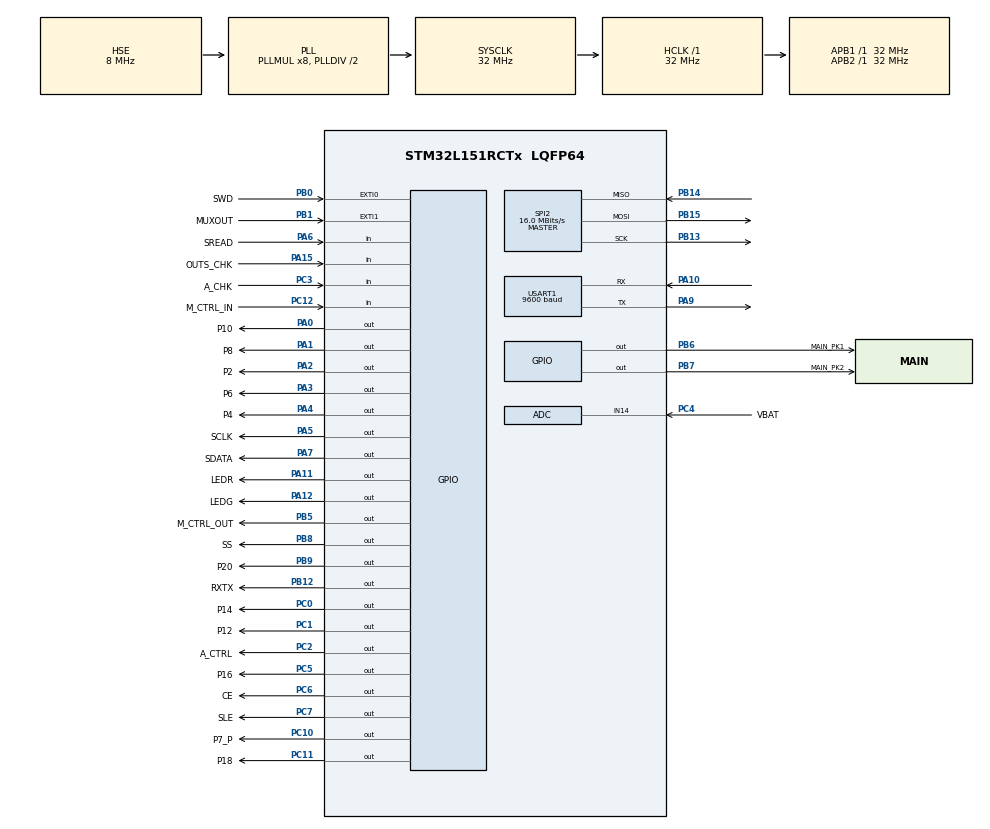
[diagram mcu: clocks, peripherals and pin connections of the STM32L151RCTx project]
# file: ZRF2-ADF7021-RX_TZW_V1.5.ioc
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ADC.Channel-0\#ChannelRegularConversion=ADC_CHANNEL_14
ADC.ContinuousConvMode=DISABLE
ADC.DataAlign=ADC_DATAALIGN_RIGHT
ADC.DiscontinuousConvMode=DISABLE
ADC.EnableAnalogWatchDog=false
ADC.ExternalTrigConv=ADC_SOFTWARE_START
ADC.InjNumberOfConversion=0
ADC.NbrOfConversion=1
ADC.Rank-0\#ChannelRegularConversion=1
ADC.SamplingTime-0\#ChannelRegularConversion=ADC_SAMPLETIME_192CYCLES
ADC.ScanConvMode=ADC_SCAN_DISABLE
Dma.ADC.0.Direction=DMA_PERIPH_TO_MEMORY
Dma.ADC.0.Instance=DMA1_Channel1
Dma.ADC.0.MemDataAlignment=DMA_MDATAALIGN_HALFWORD
Dma.ADC.0.MemInc=DMA_MINC_ENABLE
Dma.ADC.0.Mode=DMA_NORMAL
Dma.ADC.0.PeriphDataAlignment=DMA_PDATAALIGN_HALFWORD
Dma.ADC.0.PeriphInc=DMA_PINC_DISABLE
Dma.ADC.0.Priority=DMA_PRIORITY_LOW
Dma.Request0=ADC
FREERTOS.Tasks01=defaultTask,0,256,StartDefaultTask,Default,NULL,Dynamic,NULL,NULL
FREERTOS.configMAX_PRIORITIES=9
FREERTOS.configMINIMAL_STACK_SIZE=128
FREERTOS.configTOTAL_HEAP_SIZE=16000
FREERTOS.configUSE_NEWLIB_REENTRANT=1
FREERTOS.configUSE_TIMERS=1
Mcu.Family=STM32L1
Mcu.Name=STM32L151RCTx
Mcu.Package=LQFP64
NVIC.ADC1_IRQn=true\:5\:0\:false\:false\:true\:true\:true\:true\:true
NVIC.DMA1_Channel1_IRQn=true\:5\:0\:false\:false\:true\:true\:true\:true\:true
NVIC.EXTI0_IRQn=true\:5\:0\:false\:false\:true\:true\:true\:true\:true
NVIC.EXTI1_IRQn=true\:5\:0\:true\:false\:true\:true\:true\:true\:true
NVIC.PriorityGroup=NVIC_PRIORITYGROUP_4
NVIC.TIM11_IRQn=true\:5\:0\:false\:false\:true\:true\:true\:true\:true
NVIC.TIM2_IRQn=true\:15\:0\:false\:false\:true\:false\:false\:true\:true
NVIC.TimeBase=TIM2_IRQn
NVIC.TimeBaseIP=TIM2
NVIC.USART1_IRQn=true\:5\:0\:true\:false\:true\:true\:true\:true\:true
PA0-WKUP1.GPIO_Label=P10
PA0-WKUP1.Signal=GPIO_Output
PA1.GPIO_Label=P8
PA1.Signal=GPIO_Output
PA10.Mode=Asynchronous
PA10.Signal=USART1_RX
PA11.GPIO_Label=LEDR
PA11.Signal=GPIO_Output
PA12.GPIO_Label=LEDG
PA12.Signal=GPIO_Output
PA13.Mode=Serial_Wire
PA13.Signal=SYS_JTMS-SWDIO
PA14.Mode=Serial_Wire
PA14.Signal=SYS_JTCK-SWCLK
PA15.GPIO_Label=OUTS_CHK
PA15.GPIO_PuPd=GPIO_PULLUP
PA15.Signal=GPIO_Input
PA2.GPIO_Label=P2
PA2.Signal=GPIO_Output
PA3.GPIO_Label=P6
PA3.Signal=GPIO_Output
PA4.GPIO_Label=P4
PA4.Signal=GPIO_Output
PA5.GPIO_Label=SCLK
PA5.GPIO_Speed=GPIO_SPEED_FREQ_VERY_HIGH
PA5.Signal=GPIO_Output
PA6.GPIO_Label=SREAD
PA6.GPIO_PuPd=GPIO_PULLUP
PA6.Signal=GPIO_Input
PA7.GPIO_Label=SDATA
PA7.GPIO_Speed=GPIO_SPEED_FREQ_VERY_HIGH
PA7.Signal=GPIO_Output
PA9.Mode=Asynchronous
PA9.Signal=USART1_TX
PB0.GPIO_Label=SWD
PB0.GPIO_ModeDefaultEXTI=GPIO_MODE_IT_RISING
PB0.GPIO_PuPd=GPIO_NOPULL
PB0.Signal=GPXTI0
PB1.GPIO_Label=MUXOUT
PB1.GPIO_PuPd=GPIO_NOPULL
PB1.Signal=GPXTI1
PB12.GPIO_Label=RXTX
PB12.GPIO_PuPd=GPIO_NOPULL
PB12.GPIO_Speed=GPIO_SPEED_FREQ_VERY_HIGH
PB12.PinState=GPIO_PIN_RESET
PB12.Signal=GPIO_Output
PB13.Mode=Full_Duplex_Master
PB13.Signal=SPI2_SCK
PB14.Mode=Full_Duplex_Master
PB14.Signal=SPI2_MISO
PB15.Mode=Full_Duplex_Master
PB15.Signal=SPI2_MOSI
PB5.GPIO_Label=M_CTRL_OUT
PB5.GPIO_Speed=GPIO_SPEED_FREQ_MEDIUM
PB5.Signal=GPIO_Output
PB6.GPIO_Label=MAIN_PK1
PB6.Signal=GPIO_Output
PB7.GPIO_Label=MAIN_PK2
PB7.Signal=GPIO_Output
PB8.GPIO_Label=SS
PB8.GPIO_Speed=GPIO_SPEED_FREQ_VERY_HIGH
PB8.Signal=GPIO_Output
PB9.GPIO_Label=P20
PB9.Signal=GPIO_Output
PC0.GPIO_Label=P14
PC0.Signal=GPIO_Output
PC1.GPIO_Label=P12
PC1.Signal=GPIO_Output
PC10.GPIO_Label=P7_P
PC10.Signal=GPIO_Output
PC11.GPIO_Label=P18
PC11.Signal=GPIO_Output
PC12.GPIO_Label=M_CTRL_IN
PC12.GPIO_PuPd=GPIO_PULLUP
PC12.Signal=GPIO_Input
PC2.GPIO_Label=A_CTRL
PC2.PinState=GPIO_PIN_SET
PC2.Signal=GPIO_Output
PC3.GPIO_Label=A_CHK
PC3.GPIO_PuPd=GPIO_NOPULL
PC3.Signal=GPIO_Input
PC4.GPIO_Label=VBAT
PC4.Mode=IN14
PC4.Signal=ADC_IN14
PC5.GPIO_Label=P16
PC5.Signal=GPIO_Output
PC6.GPIO_Label=CE
PC6.GPIO_Speed=GPIO_SPEED_FREQ_VERY_HIGH
PC6.Signal=GPIO_Output
PC7.GPIO_Label=SLE
PC7.GPIO_Speed=GPIO_SPEED_FREQ_VERY_HIGH
PC7.Signal=GPIO_Output
PH0-OSC_IN.Mode=HSE-External-Oscillator
PH0-OSC_IN.Signal=RCC_OSC_IN
PH1-OSC_OUT.Mode=HSE-External-Oscillator
PH1-OSC_OUT.Signal=RCC_OSC_OUT
ProjectManager.HeapSize=0x200
ProjectManager.StackSize=0x400
ProjectManager.TargetToolchain=STM32CubeIDE
RCC.48MHZClocksFreq_Value=32000000
RCC.AHBFreq_Value=32000000
RCC.APB1Freq_Value=32000000
RCC.APB1TimFreq_Value=32000000
RCC.APB2Freq_Value=32000000
RCC.APB2TimFreq_Value=32000000
RCC.EnbaleCSS=true
RCC.FLatency=FLASH_LATENCY_1
RCC.HCLKFreq_Value=32000000
RCC.HSE_VALUE=8000000
RCC.HSI_VALUE=16000000
RCC.LSE_VALUE=32768
RCC.MSI_VALUE=2097000
RCC.PLLMUL=RCC_PLL_MUL8
RCC.PLLSourceVirtual=RCC_PLLSOURCE_HSE
RCC.PREFETCH_ENABLE=1
RCC.SYSCLKFreq_VALUE=32000000
RCC.SYSCLKSource=RCC_SYSCLKSOURCE_PLLCLK
RCC.VCOOutputFreq_Value=64000000
RCC.VDD_VALUE=3.3
SPI2.CalculateBaudRate=16.0 MBits/s
SPI2.Direction=SPI_DIRECTION_2LINES
SPI2.Mode=SPI_MODE_MASTER
SPI2.VirtualType=VM_MASTER
TIM11.Period=10-1
TIM11.Prescaler=32000-1
USART1.BaudRate=9600
USART1.Mode=MODE_TX_RX
USART1.OverSampling=UART_OVERSAMPLING_16
USART1.Parity=PARITY_NONE
USART1.StopBits=STOPBITS_1
USART1.VirtualMode=VM_ASYNC
USART1.WordLength=WORDLENGTH_8B
VP_FREERTOS_VS_CMSIS_V1.Mode=CMSIS_V1
VP_SYS_VS_tim2.Mode=TIM2
VP_TIM11_VS_ClockSourceINT.Mode=Internal
board=CC1120-TX_V1.21

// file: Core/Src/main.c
/* USER CODE BEGIN Header */
/**
  ******************************************************************************
  * @file           : main.c
  * @brief          : Main program body
  ******************************************************************************
  * @attention
  *
  * Copyright (c) 2022 STMicroelectronics.
  * All rights reserved.
  *
  * This software is licensed under terms that can be found in the LICENSE file
  * in the root directory of this software component.
  * If no LICENSE file comes with this software, it is provided AS-IS.
  *
  ******************************************************************************
  */
/* USER CODE END Header */
#include "main.h"
#include "cmsis_os.h"

/* USER CODE BEGIN Includes */
#include "../threads/config.h"
#include "../threads/variables.h"
#include "../threads/cmd_thread.h"
#include "../threads/ctrl_thread.h"
#include "../threads/io_ctrl_thread.h"
#include "../threads/radio_thread.h"
#include "../ADF7021/adf7021.h"
#include "../Lib/eeprom.h"

/* USER CODE END Includes */

/* USER CODE BEGIN PTD */
osThreadId ctrl_threadHandle;
osThreadId cmd_threadHandle;
osThreadId io_ctrl_threadHandle;
osThreadId radio_threadHandle;
osThreadId serial_threadHandle;
/* USER CODE END PTD */

 ADC_HandleTypeDef hadc;
DMA_HandleTypeDef hdma_adc;

SPI_HandleTypeDef hspi2;

TIM_HandleTypeDef htim11;

UART_HandleTypeDef huart1;

osThreadId defaultTaskHandle;

void SystemClock_Config(void);
static void MX_GPIO_Init(void);
static void MX_DMA_Init(void);
static void MX_USART1_UART_Init(void);
static void MX_ADC_Init(void);
static void MX_TIM11_Init(void);
static void MX_SPI2_Init(void);
void StartDefaultTask(void const * argument);

/* USER CODE BEGIN PFP */
xQueueHandle serial_tx_queue;
xQueueHandle serial_rx_queue;
xQueueHandle RF_RX_queue;
xSemaphoreHandle outputs_mutex;
xSemaphoreHandle programm_mutex;
/* USER CODE END PFP */

/* USER CODE BEGIN 0 */
static void set_inouts(void);
/* USER CODE END 0 */

int main(void)
{

  /* MCU Configuration--------------------------------------------------------*/

  /* Reset of all peripherals, Initializes the Flash interface and the Systick. */
  HAL_Init();

  /* USER CODE BEGIN Init */
	serial_tx_queue = xQueueCreate(serial_tx_queue_size, sizeof(uint8_t));
	serial_rx_queue = xQueueCreate(serial_rx_queue_size, sizeof(uint8_t));
	RF_RX_queue = xQueueCreate(128, sizeof(uint8_t));

	outputs_mutex = xSemaphoreCreateMutex();
	programm_mutex = xSemaphoreCreateMutex();

  /* USER CODE END Init */

  /* Configure the system clock */
  SystemClock_Config();

  /* Initialize all configured peripherals */
  MX_GPIO_Init();
  MX_DMA_Init();
  MX_USART1_UART_Init();
  MX_ADC_Init();
  MX_TIM11_Init();
  MX_SPI2_Init();
  /* USER CODE BEGIN 2 */
  set_inouts();
  /* USER CODE END 2 */

  /* USER CODE BEGIN RTOS_QUEUES */
  //adf_simple_init();
  /* USER CODE END RTOS_QUEUES */

  /* Create the thread(s) */
  /* definition and creation of defaultTask */
  osThreadDef(defaultTask, StartDefaultTask, osPriorityNormal, 0, 256);
  defaultTaskHandle = osThreadCreate(osThread(defaultTask), NULL);

  /* USER CODE BEGIN RTOS_THREADS */
  osThreadDef(radio_thread, radio_task, osPriorityNormal, 0, 256);
  radio_threadHandle = osThreadCreate(osThread(radio_thread), NULL);

  osThreadDef(ctrl_thread, ctrl_task, osPriorityNormal, 0, 256);
  ctrl_threadHandle = osThreadCreate(osThread(ctrl_thread), NULL);

  /* definition and creation of cmd_thread */
  osThreadDef(cmd_thread, cmd_task, osPriorityNormal, 0, 256);
  cmd_threadHandle = osThreadCreate(osThread(cmd_thread), NULL);

  /* definition and creation of io_ctrl_thread */
  osThreadDef(io_ctrl_thread, io_ctrl_task, osPriorityNormal, 0, 256);
  io_ctrl_threadHandle = osThreadCreate(osThread(io_ctrl_thread), NULL);

  /* USER CODE END RTOS_THREADS */

  /* Start scheduler */
  osKernelStart();

  /* We should never get here as control is now taken by the scheduler */
  /* Infinite loop */
  while (1)
  {

  }
}

void SystemClock_Config(void)
{
  RCC_OscInitTypeDef RCC_OscInitStruct = {0};
  RCC_ClkInitTypeDef RCC_ClkInitStruct = {0};

  /** Configure the main internal regulator output voltage
  */
  __HAL_PWR_VOLTAGESCALING_CONFIG(PWR_REGULATOR_VOLTAGE_SCALE1);

  /** Initializes the RCC Oscillators according to the specified parameters
  * in the RCC_OscInitTypeDef structure.
  */
  RCC_OscInitStruct.OscillatorType = RCC_OSCILLATORTYPE_HSI|RCC_OSCILLATORTYPE_HSE;
  RCC_OscInitStruct.HSEState = RCC_HSE_ON;
  RCC_OscInitStruct.HSIState = RCC_HSI_ON;
  RCC_OscInitStruct.HSICalibrationValue = RCC_HSICALIBRATION_DEFAULT;
  RCC_OscInitStruct.PLL.PLLState = RCC_PLL_ON;
  RCC_OscInitStruct.PLL.PLLSource = RCC_PLLSOURCE_HSE;
  RCC_OscInitStruct.PLL.PLLMUL = RCC_PLL_MUL8;
  RCC_OscInitStruct.PLL.PLLDIV = RCC_PLL_DIV2;
  if (HAL_RCC_OscConfig(&RCC_OscInitStruct) != HAL_OK)
  {
    Error_Handler();
  }

  /** Initializes the CPU, AHB and APB buses clocks
  */
  RCC_ClkInitStruct.ClockType = RCC_CLOCKTYPE_HCLK|RCC_CLOCKTYPE_SYSCLK
                              |RCC_CLOCKTYPE_PCLK1|RCC_CLOCKTYPE_PCLK2;
  RCC_ClkInitStruct.SYSCLKSource = RCC_SYSCLKSOURCE_PLLCLK;
  RCC_ClkInitStruct.AHBCLKDivider = RCC_SYSCLK_DIV1;
  RCC_ClkInitStruct.APB1CLKDivider = RCC_HCLK_DIV1;
  RCC_ClkInitStruct.APB2CLKDivider = RCC_HCLK_DIV1;

  if (HAL_RCC_ClockConfig(&RCC_ClkInitStruct, FLASH_LATENCY_1) != HAL_OK)
  {
    Error_Handler();
  }

  /** Enables the Clock Security System
  */
  HAL_RCC_EnableCSS();
}

static void MX_ADC_Init(void)
{

  ADC_ChannelConfTypeDef sConfig = {0};

  /** Configure the global features of the ADC (Clock, Resolution, Data Alignment and number of conversion)
  */
  hadc.Instance = ADC1;
  hadc.Init.ClockPrescaler = ADC_CLOCK_ASYNC_DIV1;
  hadc.Init.Resolution = ADC_RESOLUTION_12B;
  hadc.Init.DataAlign = ADC_DATAALIGN_RIGHT;
  hadc.Init.ScanConvMode = ADC_SCAN_DISABLE;
  hadc.Init.EOCSelection = ADC_EOC_SEQ_CONV;
  hadc.Init.LowPowerAutoWait = ADC_AUTOWAIT_DISABLE;
  hadc.Init.LowPowerAutoPowerOff = ADC_AUTOPOWEROFF_DISABLE;
  hadc.Init.ChannelsBank = ADC_CHANNELS_BANK_A;
  hadc.Init.ContinuousConvMode = DISABLE;
  hadc.Init.NbrOfConversion = 1;
  hadc.Init.DiscontinuousConvMode = DISABLE;
  hadc.Init.ExternalTrigConv = ADC_SOFTWARE_START;
  hadc.Init.ExternalTrigConvEdge = ADC_EXTERNALTRIGCONVEDGE_NONE;
  hadc.Init.DMAContinuousRequests = DISABLE;
  if (HAL_ADC_Init(&hadc) != HAL_OK)
  {
    Error_Handler();
  }

  /** Configure for the selected ADC regular channel its corresponding rank in the sequencer and its sample time.
  */
  sConfig.Channel = ADC_CHANNEL_14;
  sConfig.Rank = ADC_REGULAR_RANK_1;
  sConfig.SamplingTime = ADC_SAMPLETIME_192CYCLES;
  if (HAL_ADC_ConfigChannel(&hadc, &sConfig) != HAL_OK)
  {
    Error_Handler();
  }

}

static void MX_SPI2_Init(void)
{

  /* SPI2 parameter configuration*/
  hspi2.Instance = SPI2;
  hspi2.Init.Mode = SPI_MODE_MASTER;
  hspi2.Init.Direction = SPI_DIRECTION_2LINES;
  hspi2.Init.DataSize = SPI_DATASIZE_8BIT;
  hspi2.Init.CLKPolarity = SPI_POLARITY_LOW;
  hspi2.Init.CLKPhase = SPI_PHASE_1EDGE;
  hspi2.Init.NSS = SPI_NSS_SOFT;
  hspi2.Init.BaudRatePrescaler = SPI_BAUDRATEPRESCALER_2;
  hspi2.Init.FirstBit = SPI_FIRSTBIT_MSB;
  hspi2.Init.TIMode = SPI_TIMODE_DISABLE;
  hspi2.Init.CRCCalculation = SPI_CRCCALCULATION_DISABLE;
  hspi2.Init.CRCPolynomial = 10;
  if (HAL_SPI_Init(&hspi2) != HAL_OK)
  {
    Error_Handler();
  }

}

static void MX_TIM11_Init(void)
{

  TIM_ClockConfigTypeDef sClockSourceConfig = {0};

  htim11.Instance = TIM11;
  htim11.Init.Prescaler = 32000-1;
  htim11.Init.CounterMode = TIM_COUNTERMODE_UP;
  htim11.Init.Period = 10-1;
  htim11.Init.ClockDivision = TIM_CLOCKDIVISION_DIV1;
  htim11.Init.AutoReloadPreload = TIM_AUTORELOAD_PRELOAD_DISABLE;
  if (HAL_TIM_Base_Init(&htim11) != HAL_OK)
  {
    Error_Handler();
  }
  sClockSourceConfig.ClockSource = TIM_CLOCKSOURCE_INTERNAL;
  if (HAL_TIM_ConfigClockSource(&htim11, &sClockSourceConfig) != HAL_OK)
  {
    Error_Handler();
  }
  /* USER CODE BEGIN TIM11_Init 2 */
  HAL_TIM_Base_Start_IT(&htim11);
  /* USER CODE END TIM11_Init 2 */

}

static void MX_USART1_UART_Init(void)
{

  huart1.Instance = USART1;
  huart1.Init.BaudRate = 9600;
  huart1.Init.WordLength = UART_WORDLENGTH_8B;
  huart1.Init.StopBits = UART_STOPBITS_1;
  huart1.Init.Parity = UART_PARITY_NONE;
  huart1.Init.Mode = UART_MODE_TX_RX;
  huart1.Init.HwFlowCtl = UART_HWCONTROL_NONE;
  huart1.Init.OverSampling = UART_OVERSAMPLING_16;
  if (HAL_UART_Init(&huart1) != HAL_OK)
  {
    Error_Handler();
  }

}

static void MX_DMA_Init(void)
{

  /* DMA controller clock enable */
  __HAL_RCC_DMA1_CLK_ENABLE();

  /* DMA interrupt init */
  /* DMA1_Channel1_IRQn interrupt configuration */
  HAL_NVIC_SetPriority(DMA1_Channel1_IRQn, 5, 0);
  HAL_NVIC_EnableIRQ(DMA1_Channel1_IRQn);

}

static void MX_GPIO_Init(void)
{
	  GPIO_InitTypeDef GPIO_InitStruct = {0};

	  /* GPIO Ports Clock Enable */
	  __HAL_RCC_GPIOH_CLK_ENABLE();
	  __HAL_RCC_GPIOC_CLK_ENABLE();
	  __HAL_RCC_GPIOA_CLK_ENABLE();
	  __HAL_RCC_GPIOB_CLK_ENABLE();
	  __HAL_RCC_GPIOD_CLK_ENABLE();

	  /*Configure GPIO pin Output Level */
	  HAL_GPIO_WritePin(GPIOC, P14_Pin|P12_Pin|P16_Pin|CE_Pin
	                          |SLE_Pin|P7_P_Pin|P18_Pin, GPIO_PIN_RESET);

	  /*Configure GPIO pin Output Level */
	  HAL_GPIO_WritePin(A_CTRL_GPIO_Port, A_CTRL_Pin, GPIO_PIN_SET);

	  /*Configure GPIO pin Output Level */
	  HAL_GPIO_WritePin(GPIOA, P10_Pin|P8_Pin|P2_Pin|P6_Pin
	                          |P4_Pin|SCLK_Pin|SDATA_Pin|LEDR_Pin
	                          |LEDG_Pin, GPIO_PIN_RESET);

	  /*Configure GPIO pin Output Level */
	  HAL_GPIO_WritePin(GPIOB, GPIO_PIN_10|CSSS1_Pin|RXTX_Pin|MAIN_PK1_Pin
	                          |MAIN_PK2_Pin|SS_Pin|P20_Pin, GPIO_PIN_RESET);

	  /*Configure GPIO pin Output Level */
	  HAL_GPIO_WritePin(M_CTRL_OUT_GPIO_Port, M_CTRL_OUT_Pin, GPIO_PIN_RESET);

	  /*Configure GPIO pins : P14_Pin P12_Pin A_CTRL_Pin P16_Pin
	                           P7_P_Pin P18_Pin */
	  GPIO_InitStruct.Pin = P14_Pin|P12_Pin|A_CTRL_Pin|P16_Pin
	                          |P7_P_Pin|P18_Pin;
	  GPIO_InitStruct.Mode = GPIO_MODE_OUTPUT_PP;
	  GPIO_InitStruct.Pull = GPIO_NOPULL;
	  GPIO_InitStruct.Speed = GPIO_SPEED_FREQ_LOW;
	  HAL_GPIO_Init(GPIOC, &GPIO_InitStruct);

	  /*Configure GPIO pin : A_CHK_Pin */
	  GPIO_InitStruct.Pin = A_CHK_Pin;
	  GPIO_InitStruct.Mode = GPIO_MODE_INPUT;
	  GPIO_InitStruct.Pull = GPIO_NOPULL;
	  HAL_GPIO_Init(A_CHK_GPIO_Port, &GPIO_InitStruct);

	  /*Configure GPIO pins : P10_Pin P8_Pin P2_Pin P6_Pin
	                           P4_Pin LEDR_Pin LEDG_Pin */
	  GPIO_InitStruct.Pin = P10_Pin|P8_Pin|P2_Pin|P6_Pin
	                          |P4_Pin|LEDR_Pin|LEDG_Pin;
	  GPIO_InitStruct.Mode = GPIO_MODE_OUTPUT_PP;
	  GPIO_InitStruct.Pull = GPIO_NOPULL;
	  GPIO_InitStruct.Speed = GPIO_SPEED_FREQ_LOW;
	  HAL_GPIO_Init(GPIOA, &GPIO_InitStruct);

	  /*Configure GPIO pins : SCLK_Pin SDATA_Pin */
	  GPIO_InitStruct.Pin = SCLK_Pin|SDATA_Pin;
	  GPIO_InitStruct.Mode = GPIO_MODE_OUTPUT_PP;
	  GPIO_InitStruct.Pull = GPIO_NOPULL;
	  GPIO_InitStruct.Speed = GPIO_SPEED_FREQ_VERY_HIGH;
	  HAL_GPIO_Init(GPIOA, &GPIO_InitStruct);

	  /*Configure GPIO pins : SREAD_Pin OUTS_CHK_Pin */
	  GPIO_InitStruct.Pin = SREAD_Pin|OUTS_CHK_Pin;
	  GPIO_InitStruct.Mode = GPIO_MODE_INPUT;
	  GPIO_InitStruct.Pull = GPIO_PULLUP;
	  HAL_GPIO_Init(GPIOA, &GPIO_InitStruct);

	  /*Configure GPIO pins : SWD_Pin MUXOUT_Pin */
	  GPIO_InitStruct.Pin = SWD_Pin|MUXOUT_Pin;
	  GPIO_InitStruct.Mode = GPIO_MODE_IT_RISING;
	  GPIO_InitStruct.Pull = GPIO_NOPULL;
	  HAL_GPIO_Init(GPIOB, &GPIO_InitStruct);

	  /*Configure GPIO pins : PB10 CSSS1_Pin MAIN_PK1_Pin MAIN_PK2_Pin
	                           P20_Pin */
	  GPIO_InitStruct.Pin = GPIO_PIN_10|CSSS1_Pin|MAIN_PK1_Pin|MAIN_PK2_Pin
	                          |P20_Pin;
	  GPIO_InitStruct.Mode = GPIO_MODE_OUTPUT_PP;
	  GPIO_InitStruct.Pull = GPIO_NOPULL;
	  GPIO_InitStruct.Speed = GPIO_SPEED_FREQ_LOW;
	  HAL_GPIO_Init(GPIOB, &GPIO_InitStruct);

	  /*Configure GPIO pins : RXTX_Pin SS_Pin */
	  GPIO_InitStruct.Pin = RXTX_Pin|SS_Pin;
	  GPIO_InitStruct.Mode = GPIO_MODE_OUTPUT_PP;
	  GPIO_InitStruct.Pull = GPIO_NOPULL;
	  GPIO_InitStruct.Speed = GPIO_SPEED_FREQ_VERY_HIGH;
	  HAL_GPIO_Init(GPIOB, &GPIO_InitStruct);

	  /*Configure GPIO pins : CE_Pin SLE_Pin */
	  GPIO_InitStruct.Pin = CE_Pin|SLE_Pin;
	  GPIO_InitStruct.Mode = GPIO_MODE_OUTPUT_PP;
	  GPIO_InitStruct.Pull = GPIO_NOPULL;
	  GPIO_InitStruct.Speed = GPIO_SPEED_FREQ_VERY_HIGH;
	  HAL_GPIO_Init(GPIOC, &GPIO_InitStruct);

	  /*Configure GPIO pin : M_CTRL_IN_Pin */
	  GPIO_InitStruct.Pin = M_CTRL_IN_Pin;
	  GPIO_InitStruct.Mode = GPIO_MODE_INPUT;
	  GPIO_InitStruct.Pull = GPIO_PULLUP;
	  HAL_GPIO_Init(M_CTRL_IN_GPIO_Port, &GPIO_InitStruct);

	  /*Configure GPIO pin : M_CTRL_OUT_Pin */
	  GPIO_InitStruct.Pin = M_CTRL_OUT_Pin;
	  GPIO_InitStruct.Mode = GPIO_MODE_OUTPUT_PP;
	  GPIO_InitStruct.Pull = GPIO_NOPULL;
	  GPIO_InitStruct.Speed = GPIO_SPEED_FREQ_LOW;
	  HAL_GPIO_Init(M_CTRL_OUT_GPIO_Port, &GPIO_InitStruct);

	  /* EXTI interrupt init*/
	  HAL_NVIC_SetPriority(EXTI0_IRQn, 5, 0);
	  HAL_NVIC_EnableIRQ(EXTI0_IRQn);

	  HAL_NVIC_SetPriority(EXTI1_IRQn, 5, 0);
	  HAL_NVIC_EnableIRQ(EXTI1_IRQn);
}

/* USER CODE BEGIN 4 */
void set_inouts(void)
{
	for(int pos = 0; pos < 6; pos = pos + 2)
	{
	if(rx_cfg.spi_cfg[1+pos] > 0)			//0x01 wejscia  //bajty 5,4,3
	{
		SPI_numbers++;
	}
	}

  set_ios(SPI_numbers);
}
/* USER CODE END 4 */

void StartDefaultTask(void const * argument)
{
  for(;;)
  {
    osDelay(1);
  }
}

void HAL_TIM_PeriodElapsedCallback(TIM_HandleTypeDef *htim)
{
  if (htim->Instance == TIM2) {
    HAL_IncTick();
  }
}

void Error_Handler(void)
{
  __disable_irq();
  while (1)
  {
  }
}
